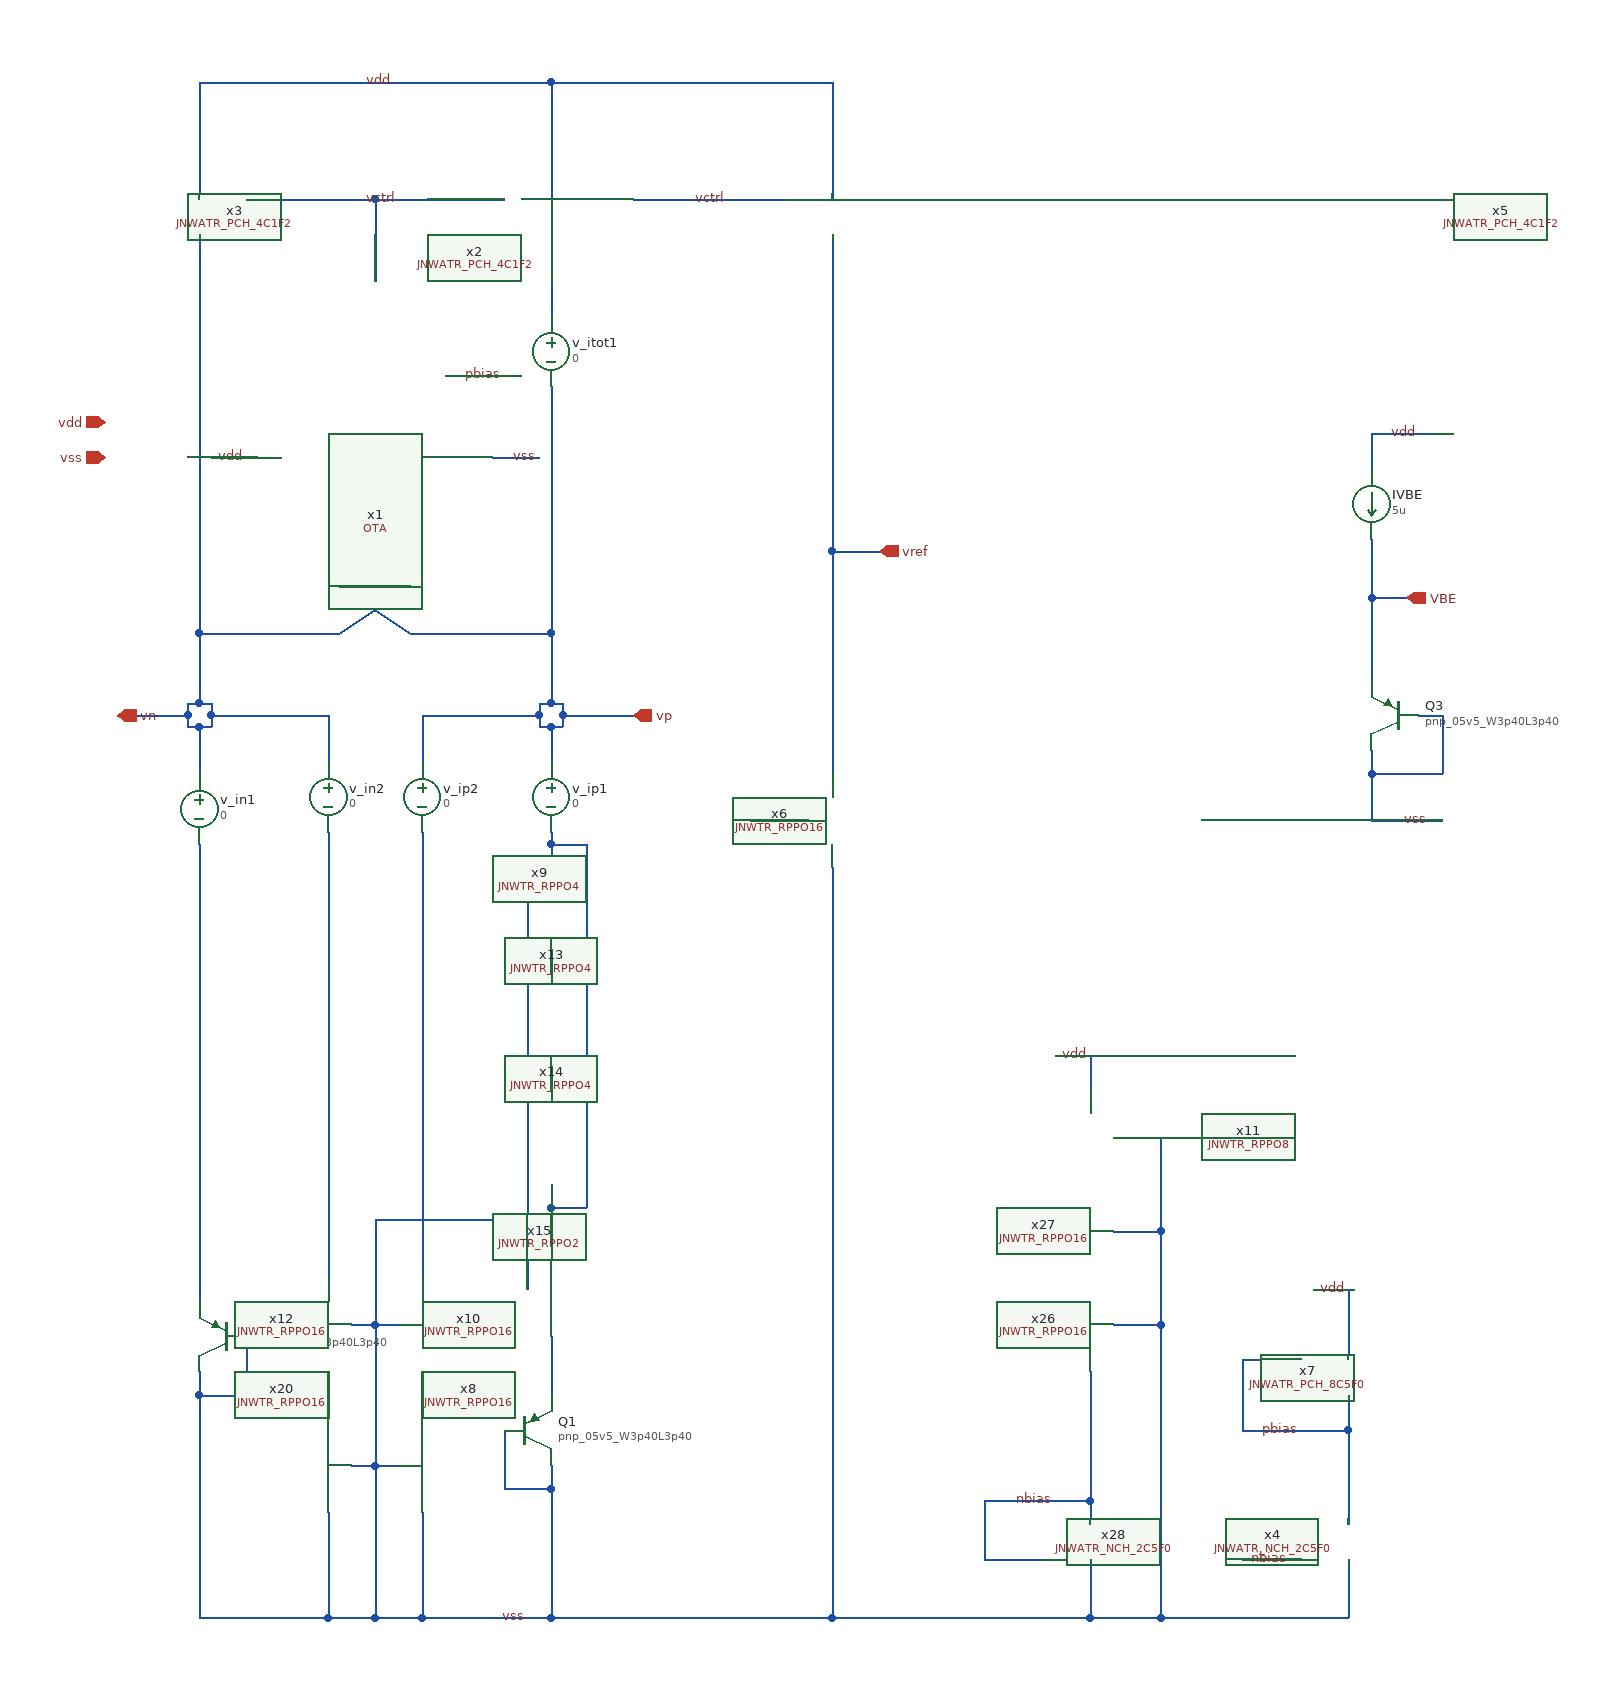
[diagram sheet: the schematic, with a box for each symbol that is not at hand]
v {xschem version=3.4.5 file_version=1.2
}
G {}
K {}
V {}
S {}
E {}
N 450 -1010 490 -1010 {
lab=vss}
N 870 -120 960 -120 {
lab=nbias}
N 960 -120 960 -100 {
lab=nbias}
N 1180 -210 1180 -180 {
lab=pbias}
N 1090 -180 1180 -180 {
lab=pbias}
N 1090 -240 1090 -180 {
lab=pbias}
N 1090 -240 1140 -240 {
lab=pbias}
N 1180 -300 1180 -240 {
lab=vdd}
N 960 -70 960 -20 {
lab=vss}
N 930 -500 960 -500 {
lab=vdd}
N 1020 -270 1020 -20 {
lab=vss}
N 980 -270 1020 -270 {
lab=vss}
N 1020 -350 1020 -270 {
lab=vss}
N 980 -350 1020 -350 {
lab=vss}
N 1020 -430 1020 -350 {
lab=vss}
N 980 -430 1020 -430 {
lab=vss}
N 960 -500 960 -470 {
lab=vdd}
N 1090 -70 1140 -70 {
lab=nbias}
N 1020 -20 1180 -20 {
lab=vss}
N 1150 -300 1180 -300 {
lab=vdd}
N 870 -120 870 -70 {
lab=nbias}
N 870 -70 920 -70 {
lab=nbias}
N 1180 -70 1180 -20 {
lab=vss}
N 1180 -180 1180 -100 {
lab=pbias}
N 410 -1080 460 -1080 {
lab=pbias}
N 960 -230 960 -120 {
lab=nbias}
N 210 -1010 250 -1010 {
lab=vdd}
N 490 -790 490 -780 {
lab=vp}
N 500 -800 510 -800 {
lab=vp}
N 210 -790 210 -780 {
lab=vn}
N 200 -800 210 -800 {
lab=vn}
N 510 -790 510 -780 {
lab=vp}
N 210 -800 210 -790 {
lab=vn}
N 490 -800 490 -790 {
lab=vp}
N 390 -790 490 -790 {
lab=vp}
N 200 -780 210 -780 {
lab=vn}
N 210 -790 310 -790 {
lab=vn}
N 190 -790 190 -780 {
lab=vn}
N 240 -260 240 -210 {
lab=vss}
N 200 -210 240 -210 {
lab=vss}
N 200 -230 200 -210 {
lab=vss}
N 460 -180 460 -130 {
lab=vss}
N 460 -130 500 -130 {
lab=vss}
N 500 -150 500 -130 {
lab=vss}
N 500 -780 510 -780 {
lab=vp}
N 380 -860 500 -860 {
lab=vp}
N 200 -860 200 -800 {
lab=vn}
N 190 -800 200 -800 {
lab=vn}
N 500 -860 500 -800 {
lab=vp}
N 490 -800 500 -800 {
lab=vp}
N 200 -1200 200 -860 {
lab=vn}
N 200 -860 320 -860 {
lab=vn}
N 350 -1230 350 -1160 {
lab=vctrl}
N 350 -1230 460 -1230 {
lab=vctrl}
N 240 -1230 350 -1230 {
lab=vctrl}
N 200 -1330 200 -1230 {
lab=vdd}
N 200 -1330 500 -1330 {
lab=vdd}
N 740 -1330 740 -1230 {
lab=vdd}
N 500 -1330 740 -1330 {
lab=vdd}
N 500 -1330 500 -1230 {
lab=vdd}
N 740 -930 740 -740 {
lab=vref}
N 510 -790 570 -790 {
lab=vp}
N 510 -800 510 -790 {
lab=vp}
N 130 -790 190 -790 {
lab=vn}
N 190 -800 190 -790 {
lab=vn}
N 740 -930 780 -930 {
lab=vref}
N 740 -1200 740 -930 {
lab=vref}
N 570 -1230 700 -1230 {
lab=vctrl}
N 500 -130 500 -20 {
lab=vss}
N 200 -210 200 -20 {
lab=vss}
N 500 -20 740 -20 {
lab=vss}
N 670 -700 720 -700 {
lab=vss}
N 740 -660 740 -20 {
lab=vss}
N 960 -20 1020 -20 {
lab=vss}
N 740 -20 960 -20 {
lab=vss}
N 390 -20 500 -20 {
lab=vss}
N 320 -900 380 -860 {
lab=vp}
N 320 -860 380 -900 {
lab=vn}
N 350 -20 390 -20 {
lab=vss}
N 310 -110 310 -20 {
lab=vss}
N 200 -20 310 -20 {
lab=vss}
N 390 -110 390 -20 {
lab=vss}
N 500 -1200 500 -1130 {
lab=#net1}
N 500 -1070 500 -860 {
lab=vp}
N 350 -150 370 -150 {
lab=vss}
N 350 -150 350 -20 {
lab=vss}
N 330 -150 350 -150 {
lab=vss}
N 310 -20 350 -20 {
lab=vss}
N 310 -230 310 -190 {
lab=#net2}
N 390 -230 390 -190 {
lab=#net3}
N 350 -270 370 -270 {
lab=vss}
N 330 -270 350 -270 {
lab=vss}
N 350 -270 350 -150 {
lab=vss}
N 500 -780 500 -750 {
lab=vp}
N 490 -780 500 -780 {
lab=vp}
N 390 -790 390 -750 {
lab=vp}
N 200 -780 200 -740 {
lab=vn}
N 190 -780 200 -780 {
lab=vn}
N 200 -680 200 -290 {
lab=#net4}
N 310 -790 310 -750 {
lab=vn}
N 1200 -890 1200 -820 {
lab=VBE}
N 1200 -740 1200 -700 {
lab=vss}
N 1200 -700 1260 -700 {
lab=vss}
N 1200 -1030 1200 -1000 {
lab=vdd}
N 1200 -1030 1250 -1030 {
lab=vdd}
N 1200 -890 1230 -890 {
lab=VBE}
N 1200 -940 1200 -890 {
lab=VBE}
N 1240 -790 1260 -790 {
lab=vss}
N 1260 -790 1260 -740 {
lab=vss}
N 1200 -740 1260 -740 {
lab=vss}
N 1200 -760 1200 -740 {
lab=vss}
N 500 -260 500 -210 {
lab=#net5}
N 500 -370 500 -340 {
lab=#net6}
N 500 -480 500 -470 {
lab=#net6}
N 500 -580 500 -570 {
lab=#net6}
N 500 -680 500 -670 {
lab=#net6}
N 480 -360 480 -300 {
lab=vss}
N 350 -360 480 -360 {
lab=vss}
N 350 -360 350 -270 {
lab=vss}
N 500 -680 530 -680 {
lab=#net6}
N 530 -480 530 -370 {
lab=#net6}
N 500 -370 530 -370 {
lab=#net6}
N 500 -390 500 -370 {
lab=#net6}
N 500 -480 530 -480 {
lab=#net6}
N 530 -580 530 -480 {
lab=#net6}
N 500 -580 530 -580 {
lab=#net6}
N 530 -680 530 -580 {
lab=#net6}
N 500 -590 500 -580 {
lab=#net6}
N 500 -490 500 -480 {
lab=#net6}
N 500 -690 500 -680 {
lab=#net6}
N 390 -690 390 -310 {
lab=#net7}
N 310 -690 310 -310 {
lab=#net8}
N 480 -630 480 -360 {
lab=vss}
C {devices/ipin.sym} 120 -1010 0 0 {name=p4 lab=vss}
C {devices/ipin.sym} 120 -1040 0 0 {name=p5 lab=vdd}
C {devices/lab_wire.sym} 1140 -180 0 0 {name=p32 sig_type=std_logic lab=pbias}
C {devices/lab_wire.sym} 960 -500 0 0 {name=p34 sig_type=std_logic lab=vdd}
C {JNW_ATR_SKY130A/JNWATR_PCH_8C5F0.sym} 1140 -240 0 0 {name=x7 }
C {JNW_ATR_SKY130A/JNWATR_NCH_2C5F0.sym} 920 -70 0 0 {name=x28 }
C {devices/lab_wire.sym} 930 -120 0 0 {name=p12 sig_type=std_logic lab=nbias}
C {devices/lab_wire.sym} 1180 -300 0 0 {name=p13 sig_type=std_logic lab=vdd}
C {JNW_ATR_SKY130A/JNWATR_NCH_2C5F0.sym} 1140 -70 0 0 {name=x4 }
C {devices/lab_wire.sym} 1130 -70 0 0 {name=p14 sig_type=std_logic lab=nbias}
C {JNW_TR_SKY130A/JNWTR_RPPO16.sym} 960 -230 3 0 {name=x26 }
C {JNW_TR_SKY130A/JNWTR_RPPO16.sym} 960 -310 3 0 {name=x27 }
C {JNW_TR_SKY130A/JNWTR_RPPO8.sym} 960 -390 3 0 {name=x11 }
C {devices/lab_wire.sym} 460 -1080 0 0 {name=p6 sig_type=std_logic lab=pbias}
C {devices/lab_wire.sym} 490 -1010 0 0 {name=p1 sig_type=std_logic lab=vss}
C {devices/lab_wire.sym} 240 -1010 0 0 {name=p2 sig_type=std_logic lab=vdd}
C {sky130_fd_pr/pnp_05v5.sym} 480 -180 0 0 {name=Q1
model=pnp_05v5_W3p40L3p40
m=8
spiceprefix=X
}
C {sky130_fd_pr/pnp_05v5.sym} 220 -260 0 1 {name=Q2
model=pnp_05v5_W3p40L3p40
m=1
spiceprefix=X
}
C {devices/lab_wire.sym} 340 -1330 0 1 {name=p29 sig_type=std_logic lab=vdd

}
C {devices/opin.sym} 130 -790 2 0 {name=p44 lab=vn}
C {JNW_ATR_SKY130A/JNWATR_PCH_4C1F2.sym} 460 -1230 0 0 {name=x2 }
C {JNW_ATR_SKY130A/JNWATR_PCH_4C1F2.sym} 240 -1230 0 1 {name=x3 }
C {JNW_ATR_SKY130A/JNWATR_PCH_4C1F2.sym} 700 -1230 0 0 {name=x5 }
C {devices/lab_wire.sym} 340 -1230 0 1 {name=p8 sig_type=std_logic lab=vctrl

}
C {devices/lab_wire.sym} 620 -1230 0 1 {name=p9 sig_type=std_logic lab=vctrl

}
C {devices/lab_wire.sym} 480 -20 0 0 {name=p3 sig_type=std_logic lab=vss
}
C {devices/opin.sym} 570 -790 0 0 {name=p7 lab=vp}
C {devices/opin.sym} 780 -930 0 0 {name=p10 lab=vref}
C {devices/lab_wire.sym} 700 -700 0 0 {name=p11 sig_type=std_logic lab=vss
}
C {JNW_AVV_SKY130A/OTA.sym} 460 -870 3 0 {name=x1}
C {JNW_TR_SKY130A/JNWTR_RPPO16.sym} 740 -740 1 0 {name=x6 }
C {JNW_TR_SKY130A/JNWTR_RPPO16.sym} 390 -190 1 0 {name=x8 }
C {JNW_TR_SKY130A/JNWTR_RPPO16.sym} 310 -190 3 1 {name=x20 }
C {devices/vsource.sym} 500 -1100 0 0 {name=v_itot1 value=0 savecurrent=true}
C {devices/vsource.sym} 500 -720 0 0 {name=v_ip1 value=0 savecurrent=true}
C {devices/vsource.sym} 390 -720 0 0 {name=v_ip2 value=0 savecurrent=true}
C {devices/vsource.sym} 200 -710 0 0 {name=v_in1 value=0 savecurrent=true}
C {devices/vsource.sym} 310 -720 0 0 {name=v_in2 value=0 savecurrent=true}
C {devices/isource.sym} 1200 -970 0 0 {name=IVBE value=5u}
C {devices/lab_wire.sym} 1240 -1030 0 0 {name=p15 sig_type=std_logic lab=vdd}
C {devices/lab_wire.sym} 1250 -700 0 0 {name=p16 sig_type=std_logic lab=vss
}
C {devices/opin.sym} 1230 -890 0 0 {name=p17 lab=VBE}
C {sky130_fd_pr/pnp_05v5.sym} 1220 -790 0 1 {name=Q3
model=pnp_05v5_W3p40L3p40
m=1
spiceprefix=X
}
C {JNW_TR_SKY130A/JNWTR_RPPO4.sym} 500 -670 1 0 {name=x9 }
C {JNW_TR_SKY130A/JNWTR_RPPO4.sym} 500 -570 1 0 {name=x13 }
C {JNW_TR_SKY130A/JNWTR_RPPO4.sym} 500 -470 1 0 {name=x14 }
C {JNW_TR_SKY130A/JNWTR_RPPO2.sym} 500 -340 1 0 {name=x15 }
C {JNW_TR_SKY130A/JNWTR_RPPO16.sym} 390 -310 1 0 {name=x10 }
C {JNW_TR_SKY130A/JNWTR_RPPO16.sym} 310 -310 3 1 {name=x12 }
